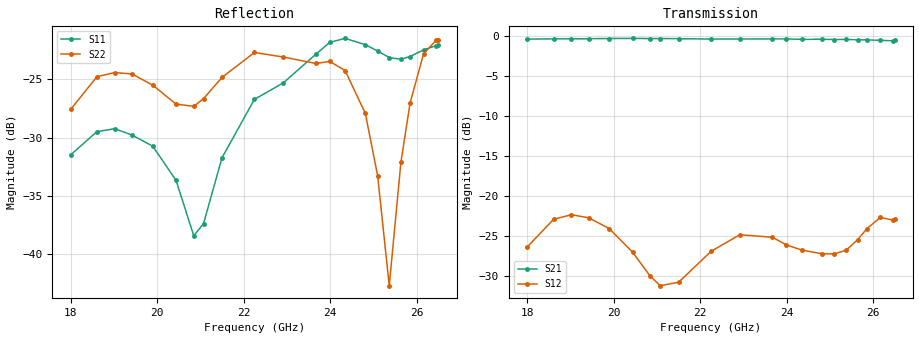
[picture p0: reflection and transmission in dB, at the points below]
! MS46524B
! 12345/M1: Not Set/M2: Not Set
! 3/11/2021 8:52:41 PM
! D:\WEBSITE FILES\DATASHEETS\MEASURED DATA\18.0 - 26.5 GHZ (D4I1826K).S2P
! CHANNEL.1
! TR.MEASUREMENT
! RAW.DATA
# GHZ S RI R 50.0
! FREQ.GHZ  S11RE  S11IM  S21RE  S21IM  S12RE  S12IM  S22RE  S22IM
!; PortSelection: Port_12
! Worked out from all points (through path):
!   601 points, 18 GHz to 26.5 GHz, reference 50 ohm
!   highest |S21| = -0.31 dB at 20.44 GHz (marker M1); lowest = -0.6 dB at 26.46 GHz (marker M2)
!   lowest |S11| = -38.4 dB at 20.85 GHz (marker M3), VSWR 1.02, Z = 51.1 + j0.536 ohm
!   |S11| at or under -10 dB: start of sweep to end of sweep
!   |S22| runs from -42.7 to -21.6 dB; largest |S21 - S12| = 1
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18  -0.0133 0.0231  -0.9548 0.0102  0.00162 0.0479  0.0193 0.037
18.60917  0.0135 0.0307  -0.7508 0.5951  0.0555 0.0449  0.0346 0.0461
19.02  0.0242 0.0246  -0.4284 0.8578  0.0762 0.00248  0.0413 0.0436
19.41667  0.0277 0.0169  -0.0399 0.959  0.0596 -0.0421  0.0445 0.0391
19.89833  0.0276 0.00912  0.4312 0.8608  0.0072 -0.062  0.043 0.0311
20.43667  0.0206 0.00261  0.8266 0.4978  -0.0362 -0.0257  0.0335 0.0285
20.8475  0.0108 0.00525  0.9557 0.1078  -0.029 0.012  0.0265 0.0339
21.07417  0.00805 0.0109  0.9548 -0.1201  -0.0135 0.0239  0.0247 0.0393
21.49917  0.0104 0.0237  0.8081 -0.5187  0.0203 0.0205  0.0282 0.0498
22.25  0.0328 0.0324  0.2033 -0.9339  0.0288 -0.0346  0.0511 0.0524
22.91583  0.0463 0.0282  -0.4419 -0.8482  -0.0277 -0.05  0.0601 0.0359
23.66667  0.0676 0.0244  -0.9135 -0.2872  -0.0534 0.0137  0.0607 0.0251
23.9925  0.0796 0.0145  -0.9569 0.0385  -0.0355 0.0343  0.065 0.0163
24.34667  0.0841 -0.00255  -0.8696 0.3854  -0.0114 0.0444  0.0612 -0.00218
24.81417  0.0766 -0.0194  -0.5798 0.7562  0.0268 0.0342  0.0358 -0.0181
25.0975  0.0702 -0.0243  -0.3231 0.8918  0.0426 0.0083  0.0144 -0.0163
25.36667  0.0658 -0.0227  -0.049 0.9493  0.0385 -0.0245  -0.00487 -0.00549
25.63583  0.0652 -0.021  0.2222 0.9186  0.011 -0.052  -0.019 0.0159
25.84833  0.0677 -0.0191  0.4285 0.8414  -0.0248 -0.0571  -0.0216 0.0389
26.16  0.0723 -0.0203  0.6857 0.6402  -0.0702 -0.021  -0.00208 0.0722
26.4575  0.0763 -0.0178  0.8521 0.3768  -0.068 0.0189  0.0348 0.0752
26.5  0.0774 -0.0159  0.873 0.3377  -0.0681 0.0219  0.0382 0.0731
